# Generated deterministically by seda-macro-lef-normalizer-v1; recipe orfs-ng45-fakeram-metal3-coupledl2-pg-v1.
VERSION 5.8 ;
BUSBITCHARS "[]" ;
DIVIDERCHAR "/" ;

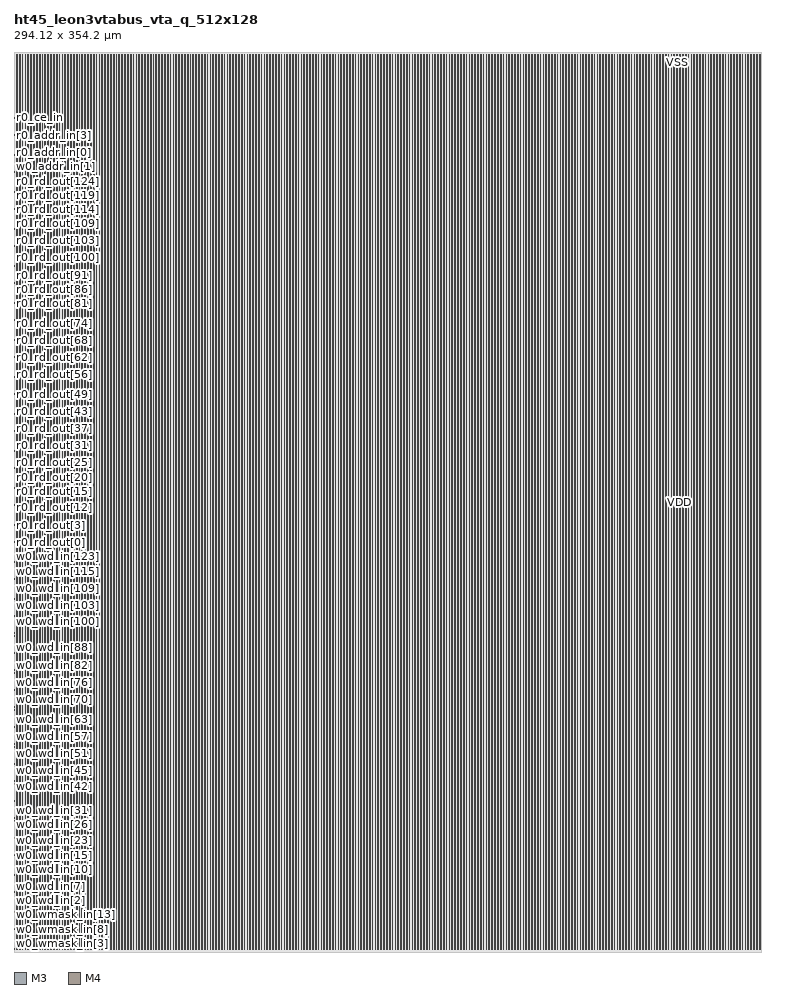
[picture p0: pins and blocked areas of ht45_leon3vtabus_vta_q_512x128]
MACRO ht45_leon3vtabus_vta_q_512x128
  FOREIGN ht45_leon3vtabus_vta_q_512x128 0 0 ;
  CLASS BLOCK ;
  ORIGIN 0 0 ;
  SIZE 294.12 BY 354.2 ;
  SYMMETRY X Y R90 ;
  PIN w0_wmask_in[0]
    DIRECTION INPUT ;
    USE SIGNAL ;
    SHAPE ABUTMENT ;
    PORT
      LAYER M3 ;
      RECT 0 0.035 0.07 0.105 ;
    END
  END w0_wmask_in[0]
  PIN w0_wmask_in[1]
    DIRECTION INPUT ;
    USE SIGNAL ;
    SHAPE ABUTMENT ;
    PORT
      LAYER M3 ;
      RECT 0 1.155 0.07 1.225 ;
    END
  END w0_wmask_in[1]
  PIN w0_wmask_in[2]
    DIRECTION INPUT ;
    USE SIGNAL ;
    SHAPE ABUTMENT ;
    PORT
      LAYER M3 ;
      RECT 0 2.275 0.07 2.345 ;
    END
  END w0_wmask_in[2]
  PIN w0_wmask_in[3]
    DIRECTION INPUT ;
    USE SIGNAL ;
    SHAPE ABUTMENT ;
    PORT
      LAYER M3 ;
      RECT 0 3.395 0.07 3.465 ;
    END
  END w0_wmask_in[3]
  PIN w0_wmask_in[4]
    DIRECTION INPUT ;
    USE SIGNAL ;
    SHAPE ABUTMENT ;
    PORT
      LAYER M3 ;
      RECT 0 4.515 0.07 4.585 ;
    END
  END w0_wmask_in[4]
  PIN w0_wmask_in[5]
    DIRECTION INPUT ;
    USE SIGNAL ;
    SHAPE ABUTMENT ;
    PORT
      LAYER M3 ;
      RECT 0 5.635 0.07 5.705 ;
    END
  END w0_wmask_in[5]
  PIN w0_wmask_in[6]
    DIRECTION INPUT ;
    USE SIGNAL ;
    SHAPE ABUTMENT ;
    PORT
      LAYER M3 ;
      RECT 0 6.755 0.07 6.825 ;
    END
  END w0_wmask_in[6]
  PIN w0_wmask_in[7]
    DIRECTION INPUT ;
    USE SIGNAL ;
    SHAPE ABUTMENT ;
    PORT
      LAYER M3 ;
      RECT 0 7.875 0.07 7.945 ;
    END
  END w0_wmask_in[7]
  PIN w0_wmask_in[8]
    DIRECTION INPUT ;
    USE SIGNAL ;
    SHAPE ABUTMENT ;
    PORT
      LAYER M3 ;
      RECT 0 8.995 0.07 9.065 ;
    END
  END w0_wmask_in[8]
  PIN w0_wmask_in[9]
    DIRECTION INPUT ;
    USE SIGNAL ;
    SHAPE ABUTMENT ;
    PORT
      LAYER M3 ;
      RECT 0 10.115 0.07 10.185 ;
    END
  END w0_wmask_in[9]
  PIN w0_wmask_in[10]
    DIRECTION INPUT ;
    USE SIGNAL ;
    SHAPE ABUTMENT ;
    PORT
      LAYER M3 ;
      RECT 0 11.235 0.07 11.305 ;
    END
  END w0_wmask_in[10]
  PIN w0_wmask_in[11]
    DIRECTION INPUT ;
    USE SIGNAL ;
    SHAPE ABUTMENT ;
    PORT
      LAYER M3 ;
      RECT 0 12.355 0.07 12.425 ;
    END
  END w0_wmask_in[11]
  PIN w0_wmask_in[12]
    DIRECTION INPUT ;
    USE SIGNAL ;
    SHAPE ABUTMENT ;
    PORT
      LAYER M3 ;
      RECT 0 13.475 0.07 13.545 ;
    END
  END w0_wmask_in[12]
  PIN w0_wmask_in[13]
    DIRECTION INPUT ;
    USE SIGNAL ;
    SHAPE ABUTMENT ;
    PORT
      LAYER M3 ;
      RECT 0 14.595 0.07 14.665 ;
    END
  END w0_wmask_in[13]
  PIN w0_wmask_in[14]
    DIRECTION INPUT ;
    USE SIGNAL ;
    SHAPE ABUTMENT ;
    PORT
      LAYER M3 ;
      RECT 0 15.715 0.07 15.785 ;
    END
  END w0_wmask_in[14]
  PIN w0_wmask_in[15]
    DIRECTION INPUT ;
    USE SIGNAL ;
    SHAPE ABUTMENT ;
    PORT
      LAYER M3 ;
      RECT 0 16.835 0.07 16.905 ;
    END
  END w0_wmask_in[15]
  PIN w0_wd_in[0]
    DIRECTION INPUT ;
    USE SIGNAL ;
    SHAPE ABUTMENT ;
    PORT
      LAYER M3 ;
      RECT 0 17.955 0.07 18.025 ;
    END
  END w0_wd_in[0]
  PIN w0_wd_in[1]
    DIRECTION INPUT ;
    USE SIGNAL ;
    SHAPE ABUTMENT ;
    PORT
      LAYER M3 ;
      RECT 0 19.075 0.07 19.145 ;
    END
  END w0_wd_in[1]
  PIN w0_wd_in[2]
    DIRECTION INPUT ;
    USE SIGNAL ;
    SHAPE ABUTMENT ;
    PORT
      LAYER M3 ;
      RECT 0 20.195 0.07 20.265 ;
    END
  END w0_wd_in[2]
  PIN w0_wd_in[3]
    DIRECTION INPUT ;
    USE SIGNAL ;
    SHAPE ABUTMENT ;
    PORT
      LAYER M3 ;
      RECT 0 21.315 0.07 21.385 ;
    END
  END w0_wd_in[3]
  PIN w0_wd_in[4]
    DIRECTION INPUT ;
    USE SIGNAL ;
    SHAPE ABUTMENT ;
    PORT
      LAYER M3 ;
      RECT 0 22.435 0.07 22.505 ;
    END
  END w0_wd_in[4]
  PIN w0_wd_in[5]
    DIRECTION INPUT ;
    USE SIGNAL ;
    SHAPE ABUTMENT ;
    PORT
      LAYER M3 ;
      RECT 0 23.555 0.07 23.625 ;
    END
  END w0_wd_in[5]
  PIN w0_wd_in[6]
    DIRECTION INPUT ;
    USE SIGNAL ;
    SHAPE ABUTMENT ;
    PORT
      LAYER M3 ;
      RECT 0 24.675 0.07 24.745 ;
    END
  END w0_wd_in[6]
  PIN w0_wd_in[7]
    DIRECTION INPUT ;
    USE SIGNAL ;
    SHAPE ABUTMENT ;
    PORT
      LAYER M3 ;
      RECT 0 25.795 0.07 25.865 ;
    END
  END w0_wd_in[7]
  PIN w0_wd_in[8]
    DIRECTION INPUT ;
    USE SIGNAL ;
    SHAPE ABUTMENT ;
    PORT
      LAYER M3 ;
      RECT 0 26.915 0.07 26.985 ;
    END
  END w0_wd_in[8]
  PIN w0_wd_in[9]
    DIRECTION INPUT ;
    USE SIGNAL ;
    SHAPE ABUTMENT ;
    PORT
      LAYER M3 ;
      RECT 0 28.035 0.07 28.105 ;
    END
  END w0_wd_in[9]
  PIN w0_wd_in[10]
    DIRECTION INPUT ;
    USE SIGNAL ;
    SHAPE ABUTMENT ;
    PORT
      LAYER M3 ;
      RECT 0 29.155 0.07 29.225 ;
    END
  END w0_wd_in[10]
  PIN w0_wd_in[11]
    DIRECTION INPUT ;
    USE SIGNAL ;
    SHAPE ABUTMENT ;
    PORT
      LAYER M3 ;
      RECT 0 30.275 0.07 30.345 ;
    END
  END w0_wd_in[11]
  PIN w0_wd_in[12]
    DIRECTION INPUT ;
    USE SIGNAL ;
    SHAPE ABUTMENT ;
    PORT
      LAYER M3 ;
      RECT 0 31.395 0.07 31.465 ;
    END
  END w0_wd_in[12]
  PIN w0_wd_in[13]
    DIRECTION INPUT ;
    USE SIGNAL ;
    SHAPE ABUTMENT ;
    PORT
      LAYER M3 ;
      RECT 0 32.515 0.07 32.585 ;
    END
  END w0_wd_in[13]
  PIN w0_wd_in[14]
    DIRECTION INPUT ;
    USE SIGNAL ;
    SHAPE ABUTMENT ;
    PORT
      LAYER M3 ;
      RECT 0 33.635 0.07 33.705 ;
    END
  END w0_wd_in[14]
  PIN w0_wd_in[15]
    DIRECTION INPUT ;
    USE SIGNAL ;
    SHAPE ABUTMENT ;
    PORT
      LAYER M3 ;
      RECT 0 34.755 0.07 34.825 ;
    END
  END w0_wd_in[15]
  PIN w0_wd_in[16]
    DIRECTION INPUT ;
    USE SIGNAL ;
    SHAPE ABUTMENT ;
    PORT
      LAYER M3 ;
      RECT 0 35.875 0.07 35.945 ;
    END
  END w0_wd_in[16]
  PIN w0_wd_in[17]
    DIRECTION INPUT ;
    USE SIGNAL ;
    SHAPE ABUTMENT ;
    PORT
      LAYER M3 ;
      RECT 0 36.995 0.07 37.065 ;
    END
  END w0_wd_in[17]
  PIN w0_wd_in[18]
    DIRECTION INPUT ;
    USE SIGNAL ;
    SHAPE ABUTMENT ;
    PORT
      LAYER M3 ;
      RECT 0 38.115 0.07 38.185 ;
    END
  END w0_wd_in[18]
  PIN w0_wd_in[19]
    DIRECTION INPUT ;
    USE SIGNAL ;
    SHAPE ABUTMENT ;
    PORT
      LAYER M3 ;
      RECT 0 39.235 0.07 39.305 ;
    END
  END w0_wd_in[19]
  PIN w0_wd_in[20]
    DIRECTION INPUT ;
    USE SIGNAL ;
    SHAPE ABUTMENT ;
    PORT
      LAYER M3 ;
      RECT 0 40.355 0.07 40.425 ;
    END
  END w0_wd_in[20]
  PIN w0_wd_in[21]
    DIRECTION INPUT ;
    USE SIGNAL ;
    SHAPE ABUTMENT ;
    PORT
      LAYER M3 ;
      RECT 0 41.475 0.07 41.545 ;
    END
  END w0_wd_in[21]
  PIN w0_wd_in[22]
    DIRECTION INPUT ;
    USE SIGNAL ;
    SHAPE ABUTMENT ;
    PORT
      LAYER M3 ;
      RECT 0 42.595 0.07 42.665 ;
    END
  END w0_wd_in[22]
  PIN w0_wd_in[23]
    DIRECTION INPUT ;
    USE SIGNAL ;
    SHAPE ABUTMENT ;
    PORT
      LAYER M3 ;
      RECT 0 43.715 0.07 43.785 ;
    END
  END w0_wd_in[23]
  PIN w0_wd_in[24]
    DIRECTION INPUT ;
    USE SIGNAL ;
    SHAPE ABUTMENT ;
    PORT
      LAYER M3 ;
      RECT 0 44.835 0.07 44.905 ;
    END
  END w0_wd_in[24]
  PIN w0_wd_in[25]
    DIRECTION INPUT ;
    USE SIGNAL ;
    SHAPE ABUTMENT ;
    PORT
      LAYER M3 ;
      RECT 0 45.955 0.07 46.025 ;
    END
  END w0_wd_in[25]
  PIN w0_wd_in[26]
    DIRECTION INPUT ;
    USE SIGNAL ;
    SHAPE ABUTMENT ;
    PORT
      LAYER M3 ;
      RECT 0 47.075 0.07 47.145 ;
    END
  END w0_wd_in[26]
  PIN w0_wd_in[27]
    DIRECTION INPUT ;
    USE SIGNAL ;
    SHAPE ABUTMENT ;
    PORT
      LAYER M3 ;
      RECT 0 48.195 0.07 48.265 ;
    END
  END w0_wd_in[27]
  PIN w0_wd_in[28]
    DIRECTION INPUT ;
    USE SIGNAL ;
    SHAPE ABUTMENT ;
    PORT
      LAYER M3 ;
      RECT 0 49.315 0.07 49.385 ;
    END
  END w0_wd_in[28]
  PIN w0_wd_in[29]
    DIRECTION INPUT ;
    USE SIGNAL ;
    SHAPE ABUTMENT ;
    PORT
      LAYER M3 ;
      RECT 0 50.435 0.07 50.505 ;
    END
  END w0_wd_in[29]
  PIN w0_wd_in[30]
    DIRECTION INPUT ;
    USE SIGNAL ;
    SHAPE ABUTMENT ;
    PORT
      LAYER M3 ;
      RECT 0 51.555 0.07 51.625 ;
    END
  END w0_wd_in[30]
  PIN w0_wd_in[31]
    DIRECTION INPUT ;
    USE SIGNAL ;
    SHAPE ABUTMENT ;
    PORT
      LAYER M3 ;
      RECT 0 52.675 0.07 52.745 ;
    END
  END w0_wd_in[31]
  PIN w0_wd_in[32]
    DIRECTION INPUT ;
    USE SIGNAL ;
    SHAPE ABUTMENT ;
    PORT
      LAYER M3 ;
      RECT 0 53.795 0.07 53.865 ;
    END
  END w0_wd_in[32]
  PIN w0_wd_in[33]
    DIRECTION INPUT ;
    USE SIGNAL ;
    SHAPE ABUTMENT ;
    PORT
      LAYER M3 ;
      RECT 0 54.915 0.07 54.985 ;
    END
  END w0_wd_in[33]
  PIN w0_wd_in[34]
    DIRECTION INPUT ;
    USE SIGNAL ;
    SHAPE ABUTMENT ;
    PORT
      LAYER M3 ;
      RECT 0 56.035 0.07 56.105 ;
    END
  END w0_wd_in[34]
  PIN w0_wd_in[35]
    DIRECTION INPUT ;
    USE SIGNAL ;
    SHAPE ABUTMENT ;
    PORT
      LAYER M3 ;
      RECT 0 57.155 0.07 57.225 ;
    END
  END w0_wd_in[35]
  PIN w0_wd_in[36]
    DIRECTION INPUT ;
    USE SIGNAL ;
    SHAPE ABUTMENT ;
    PORT
      LAYER M3 ;
      RECT 0 58.275 0.07 58.345 ;
    END
  END w0_wd_in[36]
  PIN w0_wd_in[37]
    DIRECTION INPUT ;
    USE SIGNAL ;
    SHAPE ABUTMENT ;
    PORT
      LAYER M3 ;
      RECT 0 59.395 0.07 59.465 ;
    END
  END w0_wd_in[37]
  PIN w0_wd_in[38]
    DIRECTION INPUT ;
    USE SIGNAL ;
    SHAPE ABUTMENT ;
    PORT
      LAYER M3 ;
      RECT 0 60.515 0.07 60.585 ;
    END
  END w0_wd_in[38]
  PIN w0_wd_in[39]
    DIRECTION INPUT ;
    USE SIGNAL ;
    SHAPE ABUTMENT ;
    PORT
      LAYER M3 ;
      RECT 0 61.635 0.07 61.705 ;
    END
  END w0_wd_in[39]
  PIN w0_wd_in[40]
    DIRECTION INPUT ;
    USE SIGNAL ;
    SHAPE ABUTMENT ;
    PORT
      LAYER M3 ;
      RECT 0 62.755 0.07 62.825 ;
    END
  END w0_wd_in[40]
  PIN w0_wd_in[41]
    DIRECTION INPUT ;
    USE SIGNAL ;
    SHAPE ABUTMENT ;
    PORT
      LAYER M3 ;
      RECT 0 63.875 0.07 63.945 ;
    END
  END w0_wd_in[41]
  PIN w0_wd_in[42]
    DIRECTION INPUT ;
    USE SIGNAL ;
    SHAPE ABUTMENT ;
    PORT
      LAYER M3 ;
      RECT 0 64.995 0.07 65.065 ;
    END
  END w0_wd_in[42]
  PIN w0_wd_in[43]
    DIRECTION INPUT ;
    USE SIGNAL ;
    SHAPE ABUTMENT ;
    PORT
      LAYER M3 ;
      RECT 0 66.115 0.07 66.185 ;
    END
  END w0_wd_in[43]
  PIN w0_wd_in[44]
    DIRECTION INPUT ;
    USE SIGNAL ;
    SHAPE ABUTMENT ;
    PORT
      LAYER M3 ;
      RECT 0 67.235 0.07 67.305 ;
    END
  END w0_wd_in[44]
  PIN w0_wd_in[45]
    DIRECTION INPUT ;
    USE SIGNAL ;
    SHAPE ABUTMENT ;
    PORT
      LAYER M3 ;
      RECT 0 68.355 0.07 68.425 ;
    END
  END w0_wd_in[45]
  PIN w0_wd_in[46]
    DIRECTION INPUT ;
    USE SIGNAL ;
    SHAPE ABUTMENT ;
    PORT
      LAYER M3 ;
      RECT 0 69.475 0.07 69.545 ;
    END
  END w0_wd_in[46]
  PIN w0_wd_in[47]
    DIRECTION INPUT ;
    USE SIGNAL ;
    SHAPE ABUTMENT ;
    PORT
      LAYER M3 ;
      RECT 0 70.595 0.07 70.665 ;
    END
  END w0_wd_in[47]
  PIN w0_wd_in[48]
    DIRECTION INPUT ;
    USE SIGNAL ;
    SHAPE ABUTMENT ;
    PORT
      LAYER M3 ;
      RECT 0 71.715 0.07 71.785 ;
    END
  END w0_wd_in[48]
  PIN w0_wd_in[49]
    DIRECTION INPUT ;
    USE SIGNAL ;
    SHAPE ABUTMENT ;
    PORT
      LAYER M3 ;
      RECT 0 72.835 0.07 72.905 ;
    END
  END w0_wd_in[49]
  PIN w0_wd_in[50]
    DIRECTION INPUT ;
    USE SIGNAL ;
    SHAPE ABUTMENT ;
    PORT
      LAYER M3 ;
      RECT 0 73.955 0.07 74.025 ;
    END
  END w0_wd_in[50]
  PIN w0_wd_in[51]
    DIRECTION INPUT ;
    USE SIGNAL ;
    SHAPE ABUTMENT ;
    PORT
      LAYER M3 ;
      RECT 0 75.075 0.07 75.145 ;
    END
  END w0_wd_in[51]
  PIN w0_wd_in[52]
    DIRECTION INPUT ;
    USE SIGNAL ;
    SHAPE ABUTMENT ;
    PORT
      LAYER M3 ;
      RECT 0 76.195 0.07 76.265 ;
    END
  END w0_wd_in[52]
  PIN w0_wd_in[53]
    DIRECTION INPUT ;
    USE SIGNAL ;
    SHAPE ABUTMENT ;
    PORT
      LAYER M3 ;
      RECT 0 77.315 0.07 77.385 ;
    END
  END w0_wd_in[53]
  PIN w0_wd_in[54]
    DIRECTION INPUT ;
    USE SIGNAL ;
    SHAPE ABUTMENT ;
    PORT
      LAYER M3 ;
      RECT 0 78.435 0.07 78.505 ;
    END
  END w0_wd_in[54]
  PIN w0_wd_in[55]
    DIRECTION INPUT ;
    USE SIGNAL ;
    SHAPE ABUTMENT ;
    PORT
      LAYER M3 ;
      RECT 0 79.555 0.07 79.625 ;
    END
  END w0_wd_in[55]
  PIN w0_wd_in[56]
    DIRECTION INPUT ;
    USE SIGNAL ;
    SHAPE ABUTMENT ;
    PORT
      LAYER M3 ;
      RECT 0 80.675 0.07 80.745 ;
    END
  END w0_wd_in[56]
  PIN w0_wd_in[57]
    DIRECTION INPUT ;
    USE SIGNAL ;
    SHAPE ABUTMENT ;
    PORT
      LAYER M3 ;
      RECT 0 81.795 0.07 81.865 ;
    END
  END w0_wd_in[57]
  PIN w0_wd_in[58]
    DIRECTION INPUT ;
    USE SIGNAL ;
    SHAPE ABUTMENT ;
    PORT
      LAYER M3 ;
      RECT 0 82.915 0.07 82.985 ;
    END
  END w0_wd_in[58]
  PIN w0_wd_in[59]
    DIRECTION INPUT ;
    USE SIGNAL ;
    SHAPE ABUTMENT ;
    PORT
      LAYER M3 ;
      RECT 0 84.035 0.07 84.105 ;
    END
  END w0_wd_in[59]
  PIN w0_wd_in[60]
    DIRECTION INPUT ;
    USE SIGNAL ;
    SHAPE ABUTMENT ;
    PORT
      LAYER M3 ;
      RECT 0 85.155 0.07 85.225 ;
    END
  END w0_wd_in[60]
  PIN w0_wd_in[61]
    DIRECTION INPUT ;
    USE SIGNAL ;
    SHAPE ABUTMENT ;
    PORT
      LAYER M3 ;
      RECT 0 86.275 0.07 86.345 ;
    END
  END w0_wd_in[61]
  PIN w0_wd_in[62]
    DIRECTION INPUT ;
    USE SIGNAL ;
    SHAPE ABUTMENT ;
    PORT
      LAYER M3 ;
      RECT 0 87.395 0.07 87.465 ;
    END
  END w0_wd_in[62]
  PIN w0_wd_in[63]
    DIRECTION INPUT ;
    USE SIGNAL ;
    SHAPE ABUTMENT ;
    PORT
      LAYER M3 ;
      RECT 0 88.515 0.07 88.585 ;
    END
  END w0_wd_in[63]
  PIN w0_wd_in[64]
    DIRECTION INPUT ;
    USE SIGNAL ;
    SHAPE ABUTMENT ;
    PORT
      LAYER M3 ;
      RECT 0 89.635 0.07 89.705 ;
    END
  END w0_wd_in[64]
  PIN w0_wd_in[65]
    DIRECTION INPUT ;
    USE SIGNAL ;
    SHAPE ABUTMENT ;
    PORT
      LAYER M3 ;
      RECT 0 90.755 0.07 90.825 ;
    END
  END w0_wd_in[65]
  PIN w0_wd_in[66]
    DIRECTION INPUT ;
    USE SIGNAL ;
    SHAPE ABUTMENT ;
    PORT
      LAYER M3 ;
      RECT 0 91.875 0.07 91.945 ;
    END
  END w0_wd_in[66]
  PIN w0_wd_in[67]
    DIRECTION INPUT ;
    USE SIGNAL ;
    SHAPE ABUTMENT ;
    PORT
      LAYER M3 ;
      RECT 0 92.995 0.07 93.065 ;
    END
  END w0_wd_in[67]
  PIN w0_wd_in[68]
    DIRECTION INPUT ;
    USE SIGNAL ;
    SHAPE ABUTMENT ;
    PORT
      LAYER M3 ;
      RECT 0 94.115 0.07 94.185 ;
    END
  END w0_wd_in[68]
  PIN w0_wd_in[69]
    DIRECTION INPUT ;
    USE SIGNAL ;
    SHAPE ABUTMENT ;
    PORT
      LAYER M3 ;
      RECT 0 95.235 0.07 95.305 ;
    END
  END w0_wd_in[69]
  PIN w0_wd_in[70]
    DIRECTION INPUT ;
    USE SIGNAL ;
    SHAPE ABUTMENT ;
    PORT
      LAYER M3 ;
      RECT 0 96.355 0.07 96.425 ;
    END
  END w0_wd_in[70]
  PIN w0_wd_in[71]
    DIRECTION INPUT ;
    USE SIGNAL ;
    SHAPE ABUTMENT ;
    PORT
      LAYER M3 ;
      RECT 0 97.475 0.07 97.545 ;
    END
  END w0_wd_in[71]
  PIN w0_wd_in[72]
    DIRECTION INPUT ;
    USE SIGNAL ;
    SHAPE ABUTMENT ;
    PORT
      LAYER M3 ;
      RECT 0 98.595 0.07 98.665 ;
    END
  END w0_wd_in[72]
  PIN w0_wd_in[73]
    DIRECTION INPUT ;
    USE SIGNAL ;
    SHAPE ABUTMENT ;
    PORT
      LAYER M3 ;
      RECT 0 99.715 0.07 99.785 ;
    END
  END w0_wd_in[73]
  PIN w0_wd_in[74]
    DIRECTION INPUT ;
    USE SIGNAL ;
    SHAPE ABUTMENT ;
    PORT
      LAYER M3 ;
      RECT 0 100.835 0.07 100.905 ;
    END
  END w0_wd_in[74]
  PIN w0_wd_in[75]
    DIRECTION INPUT ;
    USE SIGNAL ;
    SHAPE ABUTMENT ;
    PORT
      LAYER M3 ;
      RECT 0 101.955 0.07 102.025 ;
    END
  END w0_wd_in[75]
  PIN w0_wd_in[76]
    DIRECTION INPUT ;
    USE SIGNAL ;
    SHAPE ABUTMENT ;
    PORT
      LAYER M3 ;
      RECT 0 103.075 0.07 103.145 ;
    END
  END w0_wd_in[76]
  PIN w0_wd_in[77]
    DIRECTION INPUT ;
    USE SIGNAL ;
    SHAPE ABUTMENT ;
    PORT
      LAYER M3 ;
      RECT 0 104.195 0.07 104.265 ;
    END
  END w0_wd_in[77]
  PIN w0_wd_in[78]
    DIRECTION INPUT ;
    USE SIGNAL ;
    SHAPE ABUTMENT ;
    PORT
      LAYER M3 ;
      RECT 0 105.315 0.07 105.385 ;
    END
  END w0_wd_in[78]
  PIN w0_wd_in[79]
    DIRECTION INPUT ;
    USE SIGNAL ;
    SHAPE ABUTMENT ;
    PORT
      LAYER M3 ;
      RECT 0 106.435 0.07 106.505 ;
    END
  END w0_wd_in[79]
  PIN w0_wd_in[80]
    DIRECTION INPUT ;
    USE SIGNAL ;
    SHAPE ABUTMENT ;
    PORT
      LAYER M3 ;
      RECT 0 107.555 0.07 107.625 ;
    END
  END w0_wd_in[80]
  PIN w0_wd_in[81]
    DIRECTION INPUT ;
    USE SIGNAL ;
    SHAPE ABUTMENT ;
    PORT
      LAYER M3 ;
      RECT 0 108.675 0.07 108.745 ;
    END
  END w0_wd_in[81]
  PIN w0_wd_in[82]
    DIRECTION INPUT ;
    USE SIGNAL ;
    SHAPE ABUTMENT ;
    PORT
      LAYER M3 ;
      RECT 0 109.795 0.07 109.865 ;
    END
  END w0_wd_in[82]
  PIN w0_wd_in[83]
    DIRECTION INPUT ;
    USE SIGNAL ;
    SHAPE ABUTMENT ;
    PORT
      LAYER M3 ;
      RECT 0 110.915 0.07 110.985 ;
    END
  END w0_wd_in[83]
  PIN w0_wd_in[84]
    DIRECTION INPUT ;
    USE SIGNAL ;
    SHAPE ABUTMENT ;
    PORT
      LAYER M3 ;
      RECT 0 112.035 0.07 112.105 ;
    END
  END w0_wd_in[84]
  PIN w0_wd_in[85]
    DIRECTION INPUT ;
    USE SIGNAL ;
    SHAPE ABUTMENT ;
    PORT
      LAYER M3 ;
      RECT 0 113.155 0.07 113.225 ;
    END
  END w0_wd_in[85]
  PIN w0_wd_in[86]
    DIRECTION INPUT ;
    USE SIGNAL ;
    SHAPE ABUTMENT ;
    PORT
      LAYER M3 ;
      RECT 0 114.275 0.07 114.345 ;
    END
  END w0_wd_in[86]
  PIN w0_wd_in[87]
    DIRECTION INPUT ;
    USE SIGNAL ;
    SHAPE ABUTMENT ;
    PORT
      LAYER M3 ;
      RECT 0 115.395 0.07 115.465 ;
    END
  END w0_wd_in[87]
  PIN w0_wd_in[88]
    DIRECTION INPUT ;
    USE SIGNAL ;
    SHAPE ABUTMENT ;
    PORT
      LAYER M3 ;
      RECT 0 116.515 0.07 116.585 ;
    END
  END w0_wd_in[88]
  PIN w0_wd_in[89]
    DIRECTION INPUT ;
    USE SIGNAL ;
    SHAPE ABUTMENT ;
    PORT
      LAYER M3 ;
      RECT 0 117.635 0.07 117.705 ;
    END
  END w0_wd_in[89]
  PIN w0_wd_in[90]
    DIRECTION INPUT ;
    USE SIGNAL ;
    SHAPE ABUTMENT ;
    PORT
      LAYER M3 ;
      RECT 0 118.755 0.07 118.825 ;
    END
  END w0_wd_in[90]
  PIN w0_wd_in[91]
    DIRECTION INPUT ;
    USE SIGNAL ;
    SHAPE ABUTMENT ;
    PORT
      LAYER M3 ;
      RECT 0 119.875 0.07 119.945 ;
    END
  END w0_wd_in[91]
  PIN w0_wd_in[92]
    DIRECTION INPUT ;
    USE SIGNAL ;
    SHAPE ABUTMENT ;
    PORT
      LAYER M3 ;
      RECT 0 120.995 0.07 121.065 ;
    END
  END w0_wd_in[92]
  PIN w0_wd_in[93]
    DIRECTION INPUT ;
    USE SIGNAL ;
    SHAPE ABUTMENT ;
    PORT
      LAYER M3 ;
      RECT 0 122.115 0.07 122.185 ;
    END
  END w0_wd_in[93]
  PIN w0_wd_in[94]
    DIRECTION INPUT ;
    USE SIGNAL ;
    SHAPE ABUTMENT ;
    PORT
      LAYER M3 ;
      RECT 0 123.235 0.07 123.305 ;
    END
  END w0_wd_in[94]
  PIN w0_wd_in[95]
    DIRECTION INPUT ;
    USE SIGNAL ;
    SHAPE ABUTMENT ;
    PORT
      LAYER M3 ;
      RECT 0 124.355 0.07 124.425 ;
    END
  END w0_wd_in[95]
  PIN w0_wd_in[96]
    DIRECTION INPUT ;
    USE SIGNAL ;
    SHAPE ABUTMENT ;
    PORT
      LAYER M3 ;
      RECT 0 125.475 0.07 125.545 ;
    END
  END w0_wd_in[96]
  PIN w0_wd_in[97]
    DIRECTION INPUT ;
    USE SIGNAL ;
    SHAPE ABUTMENT ;
    PORT
      LAYER M3 ;
      RECT 0 126.595 0.07 126.665 ;
    END
  END w0_wd_in[97]
  PIN w0_wd_in[98]
    DIRECTION INPUT ;
    USE SIGNAL ;
    SHAPE ABUTMENT ;
    PORT
      LAYER M3 ;
      RECT 0 127.715 0.07 127.785 ;
    END
  END w0_wd_in[98]
  PIN w0_wd_in[99]
    DIRECTION INPUT ;
    USE SIGNAL ;
    SHAPE ABUTMENT ;
    PORT
      LAYER M3 ;
      RECT 0 128.835 0.07 128.905 ;
    END
  END w0_wd_in[99]
  PIN w0_wd_in[100]
    DIRECTION INPUT ;
    USE SIGNAL ;
    SHAPE ABUTMENT ;
    PORT
      LAYER M3 ;
      RECT 0 129.955 0.07 130.025 ;
    END
  END w0_wd_in[100]
  PIN w0_wd_in[101]
    DIRECTION INPUT ;
    USE SIGNAL ;
    SHAPE ABUTMENT ;
    PORT
      LAYER M3 ;
      RECT 0 131.075 0.07 131.145 ;
    END
  END w0_wd_in[101]
  PIN w0_wd_in[102]
    DIRECTION INPUT ;
    USE SIGNAL ;
    SHAPE ABUTMENT ;
    PORT
      LAYER M3 ;
      RECT 0 132.195 0.07 132.265 ;
    END
  END w0_wd_in[102]
  PIN w0_wd_in[103]
    DIRECTION INPUT ;
    USE SIGNAL ;
    SHAPE ABUTMENT ;
    PORT
      LAYER M3 ;
      RECT 0 133.315 0.07 133.385 ;
    END
  END w0_wd_in[103]
  PIN w0_wd_in[104]
    DIRECTION INPUT ;
    USE SIGNAL ;
    SHAPE ABUTMENT ;
    PORT
      LAYER M3 ;
      RECT 0 134.435 0.07 134.505 ;
    END
  END w0_wd_in[104]
  PIN w0_wd_in[105]
    DIRECTION INPUT ;
    USE SIGNAL ;
    SHAPE ABUTMENT ;
    PORT
      LAYER M3 ;
      RECT 0 135.555 0.07 135.625 ;
    END
  END w0_wd_in[105]
  PIN w0_wd_in[106]
    DIRECTION INPUT ;
    USE SIGNAL ;
    SHAPE ABUTMENT ;
    PORT
      LAYER M3 ;
      RECT 0 136.675 0.07 136.745 ;
    END
  END w0_wd_in[106]
  PIN w0_wd_in[107]
    DIRECTION INPUT ;
    USE SIGNAL ;
    SHAPE ABUTMENT ;
    PORT
      LAYER M3 ;
      RECT 0 137.795 0.07 137.865 ;
    END
  END w0_wd_in[107]
  PIN w0_wd_in[108]
    DIRECTION INPUT ;
    USE SIGNAL ;
    SHAPE ABUTMENT ;
    PORT
      LAYER M3 ;
      RECT 0 138.915 0.07 138.985 ;
    END
  END w0_wd_in[108]
  PIN w0_wd_in[109]
    DIRECTION INPUT ;
    USE SIGNAL ;
    SHAPE ABUTMENT ;
    PORT
      LAYER M3 ;
      RECT 0 140.035 0.07 140.105 ;
    END
  END w0_wd_in[109]
  PIN w0_wd_in[110]
    DIRECTION INPUT ;
    USE SIGNAL ;
    SHAPE ABUTMENT ;
    PORT
      LAYER M3 ;
      RECT 0 141.155 0.07 141.225 ;
    END
  END w0_wd_in[110]
  PIN w0_wd_in[111]
    DIRECTION INPUT ;
    USE SIGNAL ;
    SHAPE ABUTMENT ;
    PORT
      LAYER M3 ;
      RECT 0 142.275 0.07 142.345 ;
    END
  END w0_wd_in[111]
  PIN w0_wd_in[112]
    DIRECTION INPUT ;
    USE SIGNAL ;
    SHAPE ABUTMENT ;
    PORT
      LAYER M3 ;
      RECT 0 143.395 0.07 143.465 ;
    END
  END w0_wd_in[112]
  PIN w0_wd_in[113]
    DIRECTION INPUT ;
    USE SIGNAL ;
    SHAPE ABUTMENT ;
    PORT
      LAYER M3 ;
      RECT 0 144.515 0.07 144.585 ;
    END
  END w0_wd_in[113]
  PIN w0_wd_in[114]
    DIRECTION INPUT ;
    USE SIGNAL ;
    SHAPE ABUTMENT ;
    PORT
      LAYER M3 ;
      RECT 0 145.635 0.07 145.705 ;
    END
  END w0_wd_in[114]
  PIN w0_wd_in[115]
    DIRECTION INPUT ;
    USE SIGNAL ;
    SHAPE ABUTMENT ;
    PORT
      LAYER M3 ;
      RECT 0 146.755 0.07 146.825 ;
    END
  END w0_wd_in[115]
  PIN w0_wd_in[116]
    DIRECTION INPUT ;
    USE SIGNAL ;
    SHAPE ABUTMENT ;
    PORT
      LAYER M3 ;
      RECT 0 147.875 0.07 147.945 ;
    END
  END w0_wd_in[116]
  PIN w0_wd_in[117]
    DIRECTION INPUT ;
    USE SIGNAL ;
    SHAPE ABUTMENT ;
    PORT
      LAYER M3 ;
      RECT 0 148.995 0.07 149.065 ;
    END
  END w0_wd_in[117]
  PIN w0_wd_in[118]
    DIRECTION INPUT ;
    USE SIGNAL ;
    SHAPE ABUTMENT ;
    PORT
      LAYER M3 ;
      RECT 0 150.115 0.07 150.185 ;
    END
  END w0_wd_in[118]
  PIN w0_wd_in[119]
    DIRECTION INPUT ;
    USE SIGNAL ;
    SHAPE ABUTMENT ;
    PORT
      LAYER M3 ;
      RECT 0 151.235 0.07 151.305 ;
    END
  END w0_wd_in[119]
  PIN w0_wd_in[120]
    DIRECTION INPUT ;
    USE SIGNAL ;
    SHAPE ABUTMENT ;
    PORT
      LAYER M3 ;
      RECT 0 152.355 0.07 152.425 ;
    END
  END w0_wd_in[120]
  PIN w0_wd_in[121]
    DIRECTION INPUT ;
    USE SIGNAL ;
    SHAPE ABUTMENT ;
    PORT
      LAYER M3 ;
      RECT 0 153.475 0.07 153.545 ;
    END
  END w0_wd_in[121]
  PIN w0_wd_in[122]
    DIRECTION INPUT ;
    USE SIGNAL ;
    SHAPE ABUTMENT ;
    PORT
      LAYER M3 ;
      RECT 0 154.595 0.07 154.665 ;
    END
  END w0_wd_in[122]
  PIN w0_wd_in[123]
    DIRECTION INPUT ;
    USE SIGNAL ;
    SHAPE ABUTMENT ;
    PORT
      LAYER M3 ;
      RECT 0 155.715 0.07 155.785 ;
    END
  END w0_wd_in[123]
  PIN w0_wd_in[124]
    DIRECTION INPUT ;
    USE SIGNAL ;
    SHAPE ABUTMENT ;
    PORT
      LAYER M3 ;
      RECT 0 156.835 0.07 156.905 ;
    END
  END w0_wd_in[124]
  PIN w0_wd_in[125]
    DIRECTION INPUT ;
    USE SIGNAL ;
    SHAPE ABUTMENT ;
    PORT
      LAYER M3 ;
      RECT 0 157.955 0.07 158.025 ;
    END
  END w0_wd_in[125]
  PIN w0_wd_in[126]
    DIRECTION INPUT ;
    USE SIGNAL ;
    SHAPE ABUTMENT ;
    PORT
      LAYER M3 ;
      RECT 0 159.075 0.07 159.145 ;
    END
  END w0_wd_in[126]
  PIN w0_wd_in[127]
    DIRECTION INPUT ;
    USE SIGNAL ;
    SHAPE ABUTMENT ;
    PORT
      LAYER M3 ;
      RECT 0 160.195 0.07 160.265 ;
    END
  END w0_wd_in[127]
  PIN r0_rd_out[0]
    DIRECTION OUTPUT ;
    USE SIGNAL ;
    SHAPE ABUTMENT ;
    PORT
      LAYER M3 ;
      RECT 0 161.315 0.07 161.385 ;
    END
  END r0_rd_out[0]
  PIN r0_rd_out[1]
    DIRECTION OUTPUT ;
    USE SIGNAL ;
    SHAPE ABUTMENT ;
    PORT
      LAYER M3 ;
      RECT 0 162.435 0.07 162.505 ;
    END
  END r0_rd_out[1]
  PIN r0_rd_out[2]
    DIRECTION OUTPUT ;
    USE SIGNAL ;
    SHAPE ABUTMENT ;
    PORT
      LAYER M3 ;
      RECT 0 163.555 0.07 163.625 ;
    END
  END r0_rd_out[2]
  PIN r0_rd_out[3]
    DIRECTION OUTPUT ;
    USE SIGNAL ;
    SHAPE ABUTMENT ;
    PORT
      LAYER M3 ;
      RECT 0 164.675 0.07 164.745 ;
    END
  END r0_rd_out[3]
  PIN r0_rd_out[4]
    DIRECTION OUTPUT ;
    USE SIGNAL ;
    SHAPE ABUTMENT ;
    PORT
      LAYER M3 ;
      RECT 0 165.795 0.07 165.865 ;
    END
  END r0_rd_out[4]
  PIN r0_rd_out[5]
    DIRECTION OUTPUT ;
    USE SIGNAL ;
    SHAPE ABUTMENT ;
    PORT
      LAYER M3 ;
      RECT 0 166.915 0.07 166.985 ;
    END
  END r0_rd_out[5]
  PIN r0_rd_out[6]
    DIRECTION OUTPUT ;
    USE SIGNAL ;
    SHAPE ABUTMENT ;
    PORT
      LAYER M3 ;
      RECT 0 168.035 0.07 168.105 ;
    END
  END r0_rd_out[6]
  PIN r0_rd_out[7]
    DIRECTION OUTPUT ;
    USE SIGNAL ;
    SHAPE ABUTMENT ;
    PORT
      LAYER M3 ;
      RECT 0 169.155 0.07 169.225 ;
    END
  END r0_rd_out[7]
  PIN r0_rd_out[8]
    DIRECTION OUTPUT ;
    USE SIGNAL ;
    SHAPE ABUTMENT ;
    PORT
      LAYER M3 ;
      RECT 0 170.275 0.07 170.345 ;
    END
  END r0_rd_out[8]
  PIN r0_rd_out[9]
    DIRECTION OUTPUT ;
    USE SIGNAL ;
    SHAPE ABUTMENT ;
    PORT
      LAYER M3 ;
      RECT 0 171.395 0.07 171.465 ;
    END
  END r0_rd_out[9]
  PIN r0_rd_out[10]
    DIRECTION OUTPUT ;
    USE SIGNAL ;
    SHAPE ABUTMENT ;
    PORT
      LAYER M3 ;
      RECT 0 172.515 0.07 172.585 ;
    END
  END r0_rd_out[10]
  PIN r0_rd_out[11]
    DIRECTION OUTPUT ;
    USE SIGNAL ;
    SHAPE ABUTMENT ;
    PORT
      LAYER M3 ;
      RECT 0 173.635 0.07 173.705 ;
    END
  END r0_rd_out[11]
  PIN r0_rd_out[12]
    DIRECTION OUTPUT ;
    USE SIGNAL ;
    SHAPE ABUTMENT ;
    PORT
      LAYER M3 ;
      RECT 0 174.755 0.07 174.825 ;
    END
  END r0_rd_out[12]
  PIN r0_rd_out[13]
    DIRECTION OUTPUT ;
    USE SIGNAL ;
    SHAPE ABUTMENT ;
    PORT
      LAYER M3 ;
      RECT 0 175.875 0.07 175.945 ;
    END
  END r0_rd_out[13]
  PIN r0_rd_out[14]
    DIRECTION OUTPUT ;
    USE SIGNAL ;
    SHAPE ABUTMENT ;
    PORT
      LAYER M3 ;
      RECT 0 176.995 0.07 177.065 ;
    END
  END r0_rd_out[14]
  PIN r0_rd_out[15]
    DIRECTION OUTPUT ;
    USE SIGNAL ;
    SHAPE ABUTMENT ;
    PORT
      LAYER M3 ;
      RECT 0 178.115 0.07 178.185 ;
    END
  END r0_rd_out[15]
  PIN r0_rd_out[16]
    DIRECTION OUTPUT ;
    USE SIGNAL ;
    SHAPE ABUTMENT ;
    PORT
      LAYER M3 ;
      RECT 0 179.235 0.07 179.305 ;
    END
  END r0_rd_out[16]
  PIN r0_rd_out[17]
    DIRECTION OUTPUT ;
    USE SIGNAL ;
    SHAPE ABUTMENT ;
    PORT
      LAYER M3 ;
      RECT 0 180.355 0.07 180.425 ;
    END
  END r0_rd_out[17]
  PIN r0_rd_out[18]
    DIRECTION OUTPUT ;
    USE SIGNAL ;
    SHAPE ABUTMENT ;
    PORT
      LAYER M3 ;
      RECT 0 181.475 0.07 181.545 ;
    END
  END r0_rd_out[18]
  PIN r0_rd_out[19]
    DIRECTION OUTPUT ;
    USE SIGNAL ;
    SHAPE ABUTMENT ;
    PORT
      LAYER M3 ;
      RECT 0 182.595 0.07 182.665 ;
    END
  END r0_rd_out[19]
  PIN r0_rd_out[20]
    DIRECTION OUTPUT ;
    USE SIGNAL ;
    SHAPE ABUTMENT ;
    PORT
      LAYER M3 ;
      RECT 0 183.715 0.07 183.785 ;
    END
  END r0_rd_out[20]
  PIN r0_rd_out[21]
    DIRECTION OUTPUT ;
    USE SIGNAL ;
    SHAPE ABUTMENT ;
    PORT
      LAYER M3 ;
      RECT 0 184.835 0.07 184.905 ;
    END
  END r0_rd_out[21]
  PIN r0_rd_out[22]
    DIRECTION OUTPUT ;
    USE SIGNAL ;
    SHAPE ABUTMENT ;
    PORT
      LAYER M3 ;
      RECT 0 185.955 0.07 186.025 ;
    END
  END r0_rd_out[22]
  PIN r0_rd_out[23]
    DIRECTION OUTPUT ;
    USE SIGNAL ;
    SHAPE ABUTMENT ;
    PORT
      LAYER M3 ;
      RECT 0 187.075 0.07 187.145 ;
    END
  END r0_rd_out[23]
  PIN r0_rd_out[24]
    DIRECTION OUTPUT ;
    USE SIGNAL ;
    SHAPE ABUTMENT ;
    PORT
      LAYER M3 ;
      RECT 0 188.195 0.07 188.265 ;
    END
  END r0_rd_out[24]
  PIN r0_rd_out[25]
    DIRECTION OUTPUT ;
    USE SIGNAL ;
    SHAPE ABUTMENT ;
    PORT
      LAYER M3 ;
      RECT 0 189.315 0.07 189.385 ;
    END
  END r0_rd_out[25]
  PIN r0_rd_out[26]
    DIRECTION OUTPUT ;
    USE SIGNAL ;
    SHAPE ABUTMENT ;
    PORT
      LAYER M3 ;
      RECT 0 190.435 0.07 190.505 ;
    END
  END r0_rd_out[26]
  PIN r0_rd_out[27]
    DIRECTION OUTPUT ;
    USE SIGNAL ;
    SHAPE ABUTMENT ;
    PORT
      LAYER M3 ;
      RECT 0 191.555 0.07 191.625 ;
    END
  END r0_rd_out[27]
  PIN r0_rd_out[28]
    DIRECTION OUTPUT ;
    USE SIGNAL ;
    SHAPE ABUTMENT ;
    PORT
      LAYER M3 ;
      RECT 0 192.675 0.07 192.745 ;
    END
  END r0_rd_out[28]
  PIN r0_rd_out[29]
    DIRECTION OUTPUT ;
    USE SIGNAL ;
    SHAPE ABUTMENT ;
    PORT
      LAYER M3 ;
      RECT 0 193.795 0.07 193.865 ;
    END
  END r0_rd_out[29]
  PIN r0_rd_out[30]
    DIRECTION OUTPUT ;
    USE SIGNAL ;
    SHAPE ABUTMENT ;
    PORT
      LAYER M3 ;
      RECT 0 194.915 0.07 194.985 ;
    END
  END r0_rd_out[30]
  PIN r0_rd_out[31]
    DIRECTION OUTPUT ;
    USE SIGNAL ;
    SHAPE ABUTMENT ;
    PORT
      LAYER M3 ;
      RECT 0 196.035 0.07 196.105 ;
    END
  END r0_rd_out[31]
  PIN r0_rd_out[32]
    DIRECTION OUTPUT ;
    USE SIGNAL ;
    SHAPE ABUTMENT ;
    PORT
      LAYER M3 ;
      RECT 0 197.155 0.07 197.225 ;
    END
  END r0_rd_out[32]
  PIN r0_rd_out[33]
    DIRECTION OUTPUT ;
    USE SIGNAL ;
    SHAPE ABUTMENT ;
    PORT
      LAYER M3 ;
      RECT 0 198.275 0.07 198.345 ;
    END
  END r0_rd_out[33]
  PIN r0_rd_out[34]
    DIRECTION OUTPUT ;
    USE SIGNAL ;
    SHAPE ABUTMENT ;
    PORT
      LAYER M3 ;
      RECT 0 199.395 0.07 199.465 ;
    END
  END r0_rd_out[34]
  PIN r0_rd_out[35]
    DIRECTION OUTPUT ;
    USE SIGNAL ;
    SHAPE ABUTMENT ;
    PORT
      LAYER M3 ;
      RECT 0 200.515 0.07 200.585 ;
    END
  END r0_rd_out[35]
  PIN r0_rd_out[36]
    DIRECTION OUTPUT ;
    USE SIGNAL ;
    SHAPE ABUTMENT ;
    PORT
      LAYER M3 ;
      RECT 0 201.635 0.07 201.705 ;
    END
  END r0_rd_out[36]
  PIN r0_rd_out[37]
    DIRECTION OUTPUT ;
    USE SIGNAL ;
    SHAPE ABUTMENT ;
    PORT
      LAYER M3 ;
      RECT 0 202.755 0.07 202.825 ;
    END
  END r0_rd_out[37]
  PIN r0_rd_out[38]
    DIRECTION OUTPUT ;
    USE SIGNAL ;
    SHAPE ABUTMENT ;
    PORT
      LAYER M3 ;
      RECT 0 203.875 0.07 203.945 ;
    END
  END r0_rd_out[38]
  PIN r0_rd_out[39]
    DIRECTION OUTPUT ;
    USE SIGNAL ;
    SHAPE ABUTMENT ;
    PORT
      LAYER M3 ;
      RECT 0 204.995 0.07 205.065 ;
    END
  END r0_rd_out[39]
  PIN r0_rd_out[40]
    DIRECTION OUTPUT ;
    USE SIGNAL ;
    SHAPE ABUTMENT ;
    PORT
      LAYER M3 ;
      RECT 0 206.115 0.07 206.185 ;
    END
  END r0_rd_out[40]
  PIN r0_rd_out[41]
    DIRECTION OUTPUT ;
    USE SIGNAL ;
    SHAPE ABUTMENT ;
    PORT
      LAYER M3 ;
      RECT 0 207.235 0.07 207.305 ;
    END
  END r0_rd_out[41]
  PIN r0_rd_out[42]
    DIRECTION OUTPUT ;
    USE SIGNAL ;
    SHAPE ABUTMENT ;
    PORT
      LAYER M3 ;
      RECT 0 208.355 0.07 208.425 ;
    END
  END r0_rd_out[42]
  PIN r0_rd_out[43]
    DIRECTION OUTPUT ;
    USE SIGNAL ;
    SHAPE ABUTMENT ;
    PORT
      LAYER M3 ;
      RECT 0 209.475 0.07 209.545 ;
    END
  END r0_rd_out[43]
  PIN r0_rd_out[44]
    DIRECTION OUTPUT ;
    USE SIGNAL ;
    SHAPE ABUTMENT ;
    PORT
      LAYER M3 ;
      RECT 0 210.595 0.07 210.665 ;
    END
  END r0_rd_out[44]
  PIN r0_rd_out[45]
    DIRECTION OUTPUT ;
    USE SIGNAL ;
    SHAPE ABUTMENT ;
    PORT
      LAYER M3 ;
      RECT 0 211.715 0.07 211.785 ;
    END
  END r0_rd_out[45]
  PIN r0_rd_out[46]
    DIRECTION OUTPUT ;
    USE SIGNAL ;
    SHAPE ABUTMENT ;
    PORT
      LAYER M3 ;
      RECT 0 212.835 0.07 212.905 ;
    END
  END r0_rd_out[46]
  PIN r0_rd_out[47]
    DIRECTION OUTPUT ;
    USE SIGNAL ;
    SHAPE ABUTMENT ;
    PORT
      LAYER M3 ;
      RECT 0 213.955 0.07 214.025 ;
    END
  END r0_rd_out[47]
  PIN r0_rd_out[48]
    DIRECTION OUTPUT ;
    USE SIGNAL ;
    SHAPE ABUTMENT ;
    PORT
      LAYER M3 ;
      RECT 0 215.075 0.07 215.145 ;
    END
  END r0_rd_out[48]
  PIN r0_rd_out[49]
    DIRECTION OUTPUT ;
    USE SIGNAL ;
    SHAPE ABUTMENT ;
    PORT
      LAYER M3 ;
      RECT 0 216.195 0.07 216.265 ;
    END
  END r0_rd_out[49]
  PIN r0_rd_out[50]
    DIRECTION OUTPUT ;
    USE SIGNAL ;
    SHAPE ABUTMENT ;
    PORT
      LAYER M3 ;
      RECT 0 217.315 0.07 217.385 ;
    END
  END r0_rd_out[50]
  PIN r0_rd_out[51]
    DIRECTION OUTPUT ;
    USE SIGNAL ;
    SHAPE ABUTMENT ;
    PORT
      LAYER M3 ;
      RECT 0 218.435 0.07 218.505 ;
    END
  END r0_rd_out[51]
  PIN r0_rd_out[52]
    DIRECTION OUTPUT ;
    USE SIGNAL ;
    SHAPE ABUTMENT ;
    PORT
      LAYER M3 ;
      RECT 0 219.555 0.07 219.625 ;
    END
  END r0_rd_out[52]
  PIN r0_rd_out[53]
    DIRECTION OUTPUT ;
    USE SIGNAL ;
    SHAPE ABUTMENT ;
    PORT
      LAYER M3 ;
      RECT 0 220.675 0.07 220.745 ;
    END
  END r0_rd_out[53]
  PIN r0_rd_out[54]
    DIRECTION OUTPUT ;
    USE SIGNAL ;
    SHAPE ABUTMENT ;
    PORT
      LAYER M3 ;
      RECT 0 221.795 0.07 221.865 ;
    END
  END r0_rd_out[54]
  PIN r0_rd_out[55]
    DIRECTION OUTPUT ;
    USE SIGNAL ;
    SHAPE ABUTMENT ;
    PORT
      LAYER M3 ;
      RECT 0 222.915 0.07 222.985 ;
    END
  END r0_rd_out[55]
  PIN r0_rd_out[56]
    DIRECTION OUTPUT ;
    USE SIGNAL ;
    SHAPE ABUTMENT ;
    PORT
      LAYER M3 ;
      RECT 0 224.035 0.07 224.105 ;
    END
  END r0_rd_out[56]
  PIN r0_rd_out[57]
    DIRECTION OUTPUT ;
    USE SIGNAL ;
    SHAPE ABUTMENT ;
    PORT
      LAYER M3 ;
      RECT 0 225.155 0.07 225.225 ;
    END
  END r0_rd_out[57]
  PIN r0_rd_out[58]
    DIRECTION OUTPUT ;
    USE SIGNAL ;
    SHAPE ABUTMENT ;
    PORT
      LAYER M3 ;
      RECT 0 226.275 0.07 226.345 ;
    END
  END r0_rd_out[58]
  PIN r0_rd_out[59]
    DIRECTION OUTPUT ;
    USE SIGNAL ;
    SHAPE ABUTMENT ;
    PORT
      LAYER M3 ;
      RECT 0 227.395 0.07 227.465 ;
    END
  END r0_rd_out[59]
  PIN r0_rd_out[60]
    DIRECTION OUTPUT ;
    USE SIGNAL ;
    SHAPE ABUTMENT ;
    PORT
      LAYER M3 ;
      RECT 0 228.515 0.07 228.585 ;
    END
  END r0_rd_out[60]
  PIN r0_rd_out[61]
    DIRECTION OUTPUT ;
    USE SIGNAL ;
    SHAPE ABUTMENT ;
    PORT
      LAYER M3 ;
      RECT 0 229.635 0.07 229.705 ;
    END
  END r0_rd_out[61]
  PIN r0_rd_out[62]
    DIRECTION OUTPUT ;
    USE SIGNAL ;
    SHAPE ABUTMENT ;
    PORT
      LAYER M3 ;
      RECT 0 230.755 0.07 230.825 ;
    END
  END r0_rd_out[62]
  PIN r0_rd_out[63]
    DIRECTION OUTPUT ;
    USE SIGNAL ;
    SHAPE ABUTMENT ;
    PORT
      LAYER M3 ;
      RECT 0 231.875 0.07 231.945 ;
    END
  END r0_rd_out[63]
  PIN r0_rd_out[64]
    DIRECTION OUTPUT ;
    USE SIGNAL ;
    SHAPE ABUTMENT ;
    PORT
      LAYER M3 ;
      RECT 0 232.995 0.07 233.065 ;
    END
  END r0_rd_out[64]
  PIN r0_rd_out[65]
    DIRECTION OUTPUT ;
    USE SIGNAL ;
    SHAPE ABUTMENT ;
    PORT
      LAYER M3 ;
      RECT 0 234.115 0.07 234.185 ;
    END
  END r0_rd_out[65]
  PIN r0_rd_out[66]
    DIRECTION OUTPUT ;
    USE SIGNAL ;
    SHAPE ABUTMENT ;
    PORT
      LAYER M3 ;
      RECT 0 235.235 0.07 235.305 ;
    END
  END r0_rd_out[66]
  PIN r0_rd_out[67]
    DIRECTION OUTPUT ;
    USE SIGNAL ;
    SHAPE ABUTMENT ;
    PORT
      LAYER M3 ;
      RECT 0 236.355 0.07 236.425 ;
    END
  END r0_rd_out[67]
  PIN r0_rd_out[68]
    DIRECTION OUTPUT ;
    USE SIGNAL ;
    SHAPE ABUTMENT ;
    PORT
      LAYER M3 ;
      RECT 0 237.475 0.07 237.545 ;
    END
  END r0_rd_out[68]
  PIN r0_rd_out[69]
    DIRECTION OUTPUT ;
    USE SIGNAL ;
    SHAPE ABUTMENT ;
    PORT
      LAYER M3 ;
      RECT 0 238.595 0.07 238.665 ;
    END
  END r0_rd_out[69]
  PIN r0_rd_out[70]
    DIRECTION OUTPUT ;
    USE SIGNAL ;
    SHAPE ABUTMENT ;
    PORT
      LAYER M3 ;
      RECT 0 239.715 0.07 239.785 ;
    END
  END r0_rd_out[70]
  PIN r0_rd_out[71]
    DIRECTION OUTPUT ;
    USE SIGNAL ;
    SHAPE ABUTMENT ;
    PORT
      LAYER M3 ;
      RECT 0 240.835 0.07 240.905 ;
    END
  END r0_rd_out[71]
  PIN r0_rd_out[72]
    DIRECTION OUTPUT ;
    USE SIGNAL ;
    SHAPE ABUTMENT ;
    PORT
      LAYER M3 ;
      RECT 0 241.955 0.07 242.025 ;
    END
  END r0_rd_out[72]
  PIN r0_rd_out[73]
    DIRECTION OUTPUT ;
    USE SIGNAL ;
    SHAPE ABUTMENT ;
    PORT
      LAYER M3 ;
      RECT 0 243.075 0.07 243.145 ;
    END
  END r0_rd_out[73]
  PIN r0_rd_out[74]
    DIRECTION OUTPUT ;
    USE SIGNAL ;
    SHAPE ABUTMENT ;
    PORT
      LAYER M3 ;
      RECT 0 244.195 0.07 244.265 ;
    END
  END r0_rd_out[74]
  PIN r0_rd_out[75]
    DIRECTION OUTPUT ;
    USE SIGNAL ;
    SHAPE ABUTMENT ;
    PORT
      LAYER M3 ;
      RECT 0 245.315 0.07 245.385 ;
    END
  END r0_rd_out[75]
  PIN r0_rd_out[76]
    DIRECTION OUTPUT ;
    USE SIGNAL ;
    SHAPE ABUTMENT ;
    PORT
      LAYER M3 ;
      RECT 0 246.435 0.07 246.505 ;
    END
  END r0_rd_out[76]
  PIN r0_rd_out[77]
    DIRECTION OUTPUT ;
    USE SIGNAL ;
    SHAPE ABUTMENT ;
    PORT
      LAYER M3 ;
      RECT 0 247.555 0.07 247.625 ;
    END
  END r0_rd_out[77]
  PIN r0_rd_out[78]
    DIRECTION OUTPUT ;
    USE SIGNAL ;
    SHAPE ABUTMENT ;
    PORT
      LAYER M3 ;
      RECT 0 248.675 0.07 248.745 ;
    END
  END r0_rd_out[78]
  PIN r0_rd_out[79]
    DIRECTION OUTPUT ;
    USE SIGNAL ;
    SHAPE ABUTMENT ;
    PORT
      LAYER M3 ;
      RECT 0 249.795 0.07 249.865 ;
    END
  END r0_rd_out[79]
  PIN r0_rd_out[80]
    DIRECTION OUTPUT ;
    USE SIGNAL ;
    SHAPE ABUTMENT ;
    PORT
      LAYER M3 ;
      RECT 0 250.915 0.07 250.985 ;
    END
  END r0_rd_out[80]
  PIN r0_rd_out[81]
    DIRECTION OUTPUT ;
    USE SIGNAL ;
    SHAPE ABUTMENT ;
    PORT
      LAYER M3 ;
      RECT 0 252.035 0.07 252.105 ;
    END
  END r0_rd_out[81]
  PIN r0_rd_out[82]
    DIRECTION OUTPUT ;
    USE SIGNAL ;
    SHAPE ABUTMENT ;
    PORT
      LAYER M3 ;
      RECT 0 253.155 0.07 253.225 ;
    END
  END r0_rd_out[82]
  PIN r0_rd_out[83]
    DIRECTION OUTPUT ;
    USE SIGNAL ;
    SHAPE ABUTMENT ;
    PORT
      LAYER M3 ;
      RECT 0 254.275 0.07 254.345 ;
    END
  END r0_rd_out[83]
  PIN r0_rd_out[84]
    DIRECTION OUTPUT ;
    USE SIGNAL ;
    SHAPE ABUTMENT ;
    PORT
      LAYER M3 ;
      RECT 0 255.395 0.07 255.465 ;
    END
  END r0_rd_out[84]
  PIN r0_rd_out[85]
    DIRECTION OUTPUT ;
    USE SIGNAL ;
    SHAPE ABUTMENT ;
    PORT
      LAYER M3 ;
      RECT 0 256.515 0.07 256.585 ;
    END
  END r0_rd_out[85]
  PIN r0_rd_out[86]
    DIRECTION OUTPUT ;
    USE SIGNAL ;
    SHAPE ABUTMENT ;
    PORT
      LAYER M3 ;
      RECT 0 257.635 0.07 257.705 ;
    END
  END r0_rd_out[86]
  PIN r0_rd_out[87]
    DIRECTION OUTPUT ;
    USE SIGNAL ;
    SHAPE ABUTMENT ;
    PORT
      LAYER M3 ;
      RECT 0 258.755 0.07 258.825 ;
    END
  END r0_rd_out[87]
  PIN r0_rd_out[88]
    DIRECTION OUTPUT ;
    USE SIGNAL ;
    SHAPE ABUTMENT ;
    PORT
      LAYER M3 ;
      RECT 0 259.875 0.07 259.945 ;
    END
  END r0_rd_out[88]
  PIN r0_rd_out[89]
    DIRECTION OUTPUT ;
    USE SIGNAL ;
    SHAPE ABUTMENT ;
    PORT
      LAYER M3 ;
      RECT 0 260.995 0.07 261.065 ;
    END
  END r0_rd_out[89]
  PIN r0_rd_out[90]
    DIRECTION OUTPUT ;
    USE SIGNAL ;
    SHAPE ABUTMENT ;
    PORT
      LAYER M3 ;
      RECT 0 262.115 0.07 262.185 ;
    END
  END r0_rd_out[90]
  PIN r0_rd_out[91]
    DIRECTION OUTPUT ;
    USE SIGNAL ;
    SHAPE ABUTMENT ;
    PORT
      LAYER M3 ;
      RECT 0 263.235 0.07 263.305 ;
    END
  END r0_rd_out[91]
  PIN r0_rd_out[92]
    DIRECTION OUTPUT ;
    USE SIGNAL ;
    SHAPE ABUTMENT ;
    PORT
      LAYER M3 ;
      RECT 0 264.355 0.07 264.425 ;
    END
  END r0_rd_out[92]
  PIN r0_rd_out[93]
    DIRECTION OUTPUT ;
    USE SIGNAL ;
    SHAPE ABUTMENT ;
    PORT
      LAYER M3 ;
      RECT 0 265.475 0.07 265.545 ;
    END
  END r0_rd_out[93]
  PIN r0_rd_out[94]
    DIRECTION OUTPUT ;
    USE SIGNAL ;
    SHAPE ABUTMENT ;
    PORT
      LAYER M3 ;
      RECT 0 266.595 0.07 266.665 ;
    END
  END r0_rd_out[94]
  PIN r0_rd_out[95]
    DIRECTION OUTPUT ;
    USE SIGNAL ;
    SHAPE ABUTMENT ;
    PORT
      LAYER M3 ;
      RECT 0 267.715 0.07 267.785 ;
    END
  END r0_rd_out[95]
  PIN r0_rd_out[96]
    DIRECTION OUTPUT ;
    USE SIGNAL ;
    SHAPE ABUTMENT ;
    PORT
      LAYER M3 ;
      RECT 0 268.835 0.07 268.905 ;
    END
  END r0_rd_out[96]
  PIN r0_rd_out[97]
    DIRECTION OUTPUT ;
    USE SIGNAL ;
    SHAPE ABUTMENT ;
    PORT
      LAYER M3 ;
      RECT 0 269.955 0.07 270.025 ;
    END
  END r0_rd_out[97]
  PIN r0_rd_out[98]
    DIRECTION OUTPUT ;
    USE SIGNAL ;
    SHAPE ABUTMENT ;
    PORT
      LAYER M3 ;
      RECT 0 271.075 0.07 271.145 ;
    END
  END r0_rd_out[98]
  PIN r0_rd_out[99]
    DIRECTION OUTPUT ;
    USE SIGNAL ;
    SHAPE ABUTMENT ;
    PORT
      LAYER M3 ;
      RECT 0 272.195 0.07 272.265 ;
    END
  END r0_rd_out[99]
  PIN r0_rd_out[100]
    DIRECTION OUTPUT ;
    USE SIGNAL ;
    SHAPE ABUTMENT ;
    PORT
      LAYER M3 ;
      RECT 0 273.315 0.07 273.385 ;
    END
  END r0_rd_out[100]
  PIN r0_rd_out[101]
    DIRECTION OUTPUT ;
    USE SIGNAL ;
    SHAPE ABUTMENT ;
    PORT
      LAYER M3 ;
      RECT 0 274.435 0.07 274.505 ;
    END
  END r0_rd_out[101]
  PIN r0_rd_out[102]
    DIRECTION OUTPUT ;
    USE SIGNAL ;
    SHAPE ABUTMENT ;
    PORT
      LAYER M3 ;
      RECT 0 275.555 0.07 275.625 ;
    END
  END r0_rd_out[102]
  PIN r0_rd_out[103]
    DIRECTION OUTPUT ;
    USE SIGNAL ;
    SHAPE ABUTMENT ;
    PORT
      LAYER M3 ;
      RECT 0 276.675 0.07 276.745 ;
    END
  END r0_rd_out[103]
  PIN r0_rd_out[104]
    DIRECTION OUTPUT ;
    USE SIGNAL ;
    SHAPE ABUTMENT ;
    PORT
      LAYER M3 ;
      RECT 0 277.795 0.07 277.865 ;
    END
  END r0_rd_out[104]
  PIN r0_rd_out[105]
    DIRECTION OUTPUT ;
    USE SIGNAL ;
    SHAPE ABUTMENT ;
    PORT
      LAYER M3 ;
      RECT 0 278.915 0.07 278.985 ;
    END
  END r0_rd_out[105]
  PIN r0_rd_out[106]
    DIRECTION OUTPUT ;
    USE SIGNAL ;
    SHAPE ABUTMENT ;
    PORT
      LAYER M3 ;
      RECT 0 280.035 0.07 280.105 ;
    END
  END r0_rd_out[106]
  PIN r0_rd_out[107]
    DIRECTION OUTPUT ;
    USE SIGNAL ;
    SHAPE ABUTMENT ;
    PORT
      LAYER M3 ;
      RECT 0 281.155 0.07 281.225 ;
    END
  END r0_rd_out[107]
  PIN r0_rd_out[108]
    DIRECTION OUTPUT ;
    USE SIGNAL ;
    SHAPE ABUTMENT ;
    PORT
      LAYER M3 ;
      RECT 0 282.275 0.07 282.345 ;
    END
  END r0_rd_out[108]
  PIN r0_rd_out[109]
    DIRECTION OUTPUT ;
    USE SIGNAL ;
    SHAPE ABUTMENT ;
    PORT
      LAYER M3 ;
      RECT 0 283.395 0.07 283.465 ;
    END
  END r0_rd_out[109]
  PIN r0_rd_out[110]
    DIRECTION OUTPUT ;
    USE SIGNAL ;
    SHAPE ABUTMENT ;
    PORT
      LAYER M3 ;
      RECT 0 284.515 0.07 284.585 ;
    END
  END r0_rd_out[110]
  PIN r0_rd_out[111]
    DIRECTION OUTPUT ;
    USE SIGNAL ;
    SHAPE ABUTMENT ;
    PORT
      LAYER M3 ;
      RECT 0 285.635 0.07 285.705 ;
    END
  END r0_rd_out[111]
  PIN r0_rd_out[112]
    DIRECTION OUTPUT ;
    USE SIGNAL ;
    SHAPE ABUTMENT ;
    PORT
      LAYER M3 ;
      RECT 0 286.755 0.07 286.825 ;
    END
  END r0_rd_out[112]
  PIN r0_rd_out[113]
    DIRECTION OUTPUT ;
    USE SIGNAL ;
    SHAPE ABUTMENT ;
    PORT
      LAYER M3 ;
      RECT 0 287.875 0.07 287.945 ;
    END
  END r0_rd_out[113]
  PIN r0_rd_out[114]
    DIRECTION OUTPUT ;
    USE SIGNAL ;
    SHAPE ABUTMENT ;
    PORT
      LAYER M3 ;
      RECT 0 288.995 0.07 289.065 ;
    END
  END r0_rd_out[114]
  PIN r0_rd_out[115]
    DIRECTION OUTPUT ;
    USE SIGNAL ;
    SHAPE ABUTMENT ;
    PORT
      LAYER M3 ;
      RECT 0 290.115 0.07 290.185 ;
    END
  END r0_rd_out[115]
  PIN r0_rd_out[116]
    DIRECTION OUTPUT ;
    USE SIGNAL ;
    SHAPE ABUTMENT ;
    PORT
      LAYER M3 ;
      RECT 0 291.235 0.07 291.305 ;
    END
  END r0_rd_out[116]
  PIN r0_rd_out[117]
    DIRECTION OUTPUT ;
    USE SIGNAL ;
    SHAPE ABUTMENT ;
    PORT
      LAYER M3 ;
      RECT 0 292.355 0.07 292.425 ;
    END
  END r0_rd_out[117]
  PIN r0_rd_out[118]
    DIRECTION OUTPUT ;
    USE SIGNAL ;
    SHAPE ABUTMENT ;
    PORT
      LAYER M3 ;
      RECT 0 293.475 0.07 293.545 ;
    END
  END r0_rd_out[118]
  PIN r0_rd_out[119]
    DIRECTION OUTPUT ;
    USE SIGNAL ;
    SHAPE ABUTMENT ;
    PORT
      LAYER M3 ;
      RECT 0 294.595 0.07 294.665 ;
    END
  END r0_rd_out[119]
  PIN r0_rd_out[120]
    DIRECTION OUTPUT ;
    USE SIGNAL ;
    SHAPE ABUTMENT ;
    PORT
      LAYER M3 ;
      RECT 0 295.715 0.07 295.785 ;
    END
  END r0_rd_out[120]
  PIN r0_rd_out[121]
    DIRECTION OUTPUT ;
    USE SIGNAL ;
    SHAPE ABUTMENT ;
    PORT
      LAYER M3 ;
      RECT 0 296.835 0.07 296.905 ;
    END
  END r0_rd_out[121]
  PIN r0_rd_out[122]
    DIRECTION OUTPUT ;
    USE SIGNAL ;
    SHAPE ABUTMENT ;
    PORT
      LAYER M3 ;
      RECT 0 297.955 0.07 298.025 ;
    END
  END r0_rd_out[122]
  PIN r0_rd_out[123]
    DIRECTION OUTPUT ;
    USE SIGNAL ;
    SHAPE ABUTMENT ;
    PORT
      LAYER M3 ;
      RECT 0 299.075 0.07 299.145 ;
    END
  END r0_rd_out[123]
  PIN r0_rd_out[124]
    DIRECTION OUTPUT ;
    USE SIGNAL ;
    SHAPE ABUTMENT ;
    PORT
      LAYER M3 ;
      RECT 0 300.195 0.07 300.265 ;
    END
  END r0_rd_out[124]
  PIN r0_rd_out[125]
    DIRECTION OUTPUT ;
    USE SIGNAL ;
    SHAPE ABUTMENT ;
    PORT
      LAYER M3 ;
      RECT 0 301.315 0.07 301.385 ;
    END
  END r0_rd_out[125]
  PIN r0_rd_out[126]
    DIRECTION OUTPUT ;
    USE SIGNAL ;
    SHAPE ABUTMENT ;
    PORT
      LAYER M3 ;
      RECT 0 302.435 0.07 302.505 ;
    END
  END r0_rd_out[126]
  PIN r0_rd_out[127]
    DIRECTION OUTPUT ;
    USE SIGNAL ;
    SHAPE ABUTMENT ;
    PORT
      LAYER M3 ;
      RECT 0 303.555 0.07 303.625 ;
    END
  END r0_rd_out[127]
  PIN w0_addr_in[0]
    DIRECTION INPUT ;
    USE SIGNAL ;
    SHAPE ABUTMENT ;
    PORT
      LAYER M3 ;
      RECT 0 304.675 0.07 304.745 ;
    END
  END w0_addr_in[0]
  PIN w0_addr_in[1]
    DIRECTION INPUT ;
    USE SIGNAL ;
    SHAPE ABUTMENT ;
    PORT
      LAYER M3 ;
      RECT 0 305.795 0.07 305.865 ;
    END
  END w0_addr_in[1]
  PIN w0_addr_in[2]
    DIRECTION INPUT ;
    USE SIGNAL ;
    SHAPE ABUTMENT ;
    PORT
      LAYER M3 ;
      RECT 0 306.915 0.07 306.985 ;
    END
  END w0_addr_in[2]
  PIN w0_addr_in[3]
    DIRECTION INPUT ;
    USE SIGNAL ;
    SHAPE ABUTMENT ;
    PORT
      LAYER M3 ;
      RECT 0 308.035 0.07 308.105 ;
    END
  END w0_addr_in[3]
  PIN w0_addr_in[4]
    DIRECTION INPUT ;
    USE SIGNAL ;
    SHAPE ABUTMENT ;
    PORT
      LAYER M3 ;
      RECT 0 309.155 0.07 309.225 ;
    END
  END w0_addr_in[4]
  PIN w0_addr_in[5]
    DIRECTION INPUT ;
    USE SIGNAL ;
    SHAPE ABUTMENT ;
    PORT
      LAYER M3 ;
      RECT 0 310.275 0.07 310.345 ;
    END
  END w0_addr_in[5]
  PIN w0_addr_in[6]
    DIRECTION INPUT ;
    USE SIGNAL ;
    SHAPE ABUTMENT ;
    PORT
      LAYER M3 ;
      RECT 0 311.395 0.07 311.465 ;
    END
  END w0_addr_in[6]
  PIN w0_addr_in[7]
    DIRECTION INPUT ;
    USE SIGNAL ;
    SHAPE ABUTMENT ;
    PORT
      LAYER M3 ;
      RECT 0 312.515 0.07 312.585 ;
    END
  END w0_addr_in[7]
  PIN w0_addr_in[8]
    DIRECTION INPUT ;
    USE SIGNAL ;
    SHAPE ABUTMENT ;
    PORT
      LAYER M3 ;
      RECT 0 313.635 0.07 313.705 ;
    END
  END w0_addr_in[8]
  PIN r0_addr_in[0]
    DIRECTION INPUT ;
    USE SIGNAL ;
    SHAPE ABUTMENT ;
    PORT
      LAYER M3 ;
      RECT 0 314.755 0.07 314.825 ;
    END
  END r0_addr_in[0]
  PIN r0_addr_in[1]
    DIRECTION INPUT ;
    USE SIGNAL ;
    SHAPE ABUTMENT ;
    PORT
      LAYER M3 ;
      RECT 0 315.875 0.07 315.945 ;
    END
  END r0_addr_in[1]
  PIN r0_addr_in[2]
    DIRECTION INPUT ;
    USE SIGNAL ;
    SHAPE ABUTMENT ;
    PORT
      LAYER M3 ;
      RECT 0 316.995 0.07 317.065 ;
    END
  END r0_addr_in[2]
  PIN r0_addr_in[3]
    DIRECTION INPUT ;
    USE SIGNAL ;
    SHAPE ABUTMENT ;
    PORT
      LAYER M3 ;
      RECT 0 318.115 0.07 318.185 ;
    END
  END r0_addr_in[3]
  PIN r0_addr_in[4]
    DIRECTION INPUT ;
    USE SIGNAL ;
    SHAPE ABUTMENT ;
    PORT
      LAYER M3 ;
      RECT 0 319.235 0.07 319.305 ;
    END
  END r0_addr_in[4]
  PIN r0_addr_in[5]
    DIRECTION INPUT ;
    USE SIGNAL ;
    SHAPE ABUTMENT ;
    PORT
      LAYER M3 ;
      RECT 0 320.355 0.07 320.425 ;
    END
  END r0_addr_in[5]
  PIN r0_addr_in[6]
    DIRECTION INPUT ;
    USE SIGNAL ;
    SHAPE ABUTMENT ;
    PORT
      LAYER M3 ;
      RECT 0 321.475 0.07 321.545 ;
    END
  END r0_addr_in[6]
  PIN r0_addr_in[7]
    DIRECTION INPUT ;
    USE SIGNAL ;
    SHAPE ABUTMENT ;
    PORT
      LAYER M3 ;
      RECT 0 322.595 0.07 322.665 ;
    END
  END r0_addr_in[7]
  PIN r0_addr_in[8]
    DIRECTION INPUT ;
    USE SIGNAL ;
    SHAPE ABUTMENT ;
    PORT
      LAYER M3 ;
      RECT 0 323.715 0.07 323.785 ;
    END
  END r0_addr_in[8]
  PIN w0_we_in
    DIRECTION INPUT ;
    USE SIGNAL ;
    SHAPE ABUTMENT ;
    PORT
      LAYER M3 ;
      RECT 0 324.835 0.07 324.905 ;
    END
  END w0_we_in
  PIN w0_ce_in
    DIRECTION INPUT ;
    USE SIGNAL ;
    SHAPE ABUTMENT ;
    PORT
      LAYER M3 ;
      RECT 0 325.955 0.07 326.025 ;
    END
  END w0_ce_in
  PIN w0_clk
    DIRECTION INPUT ;
    USE SIGNAL ;
    SHAPE ABUTMENT ;
    PORT
      LAYER M3 ;
      RECT 0 327.075 0.07 327.145 ;
    END
  END w0_clk
  PIN r0_ce_in
    DIRECTION INPUT ;
    USE SIGNAL ;
    SHAPE ABUTMENT ;
    PORT
      LAYER M3 ;
      RECT 0 328.195 0.07 328.265 ;
    END
  END r0_ce_in
  PIN r0_clk
    DIRECTION INPUT ;
    USE SIGNAL ;
    SHAPE ABUTMENT ;
    PORT
      LAYER M3 ;
      RECT 0 329.315 0.07 329.385 ;
    END
  END r0_clk
  PIN VSS
    DIRECTION INOUT ;
    USE GROUND ;
    PORT
      LAYER M4 ;
      RECT 1 0.84 1.28 353.36 ;
      RECT 3.24 0.84 3.52 353.36 ;
      RECT 5.48 0.84 5.76 353.36 ;
      RECT 7.72 0.84 8 353.36 ;
      RECT 9.96 0.84 10.24 353.36 ;
      RECT 12.2 0.84 12.48 353.36 ;
      RECT 14.44 0.84 14.72 353.36 ;
      RECT 16.68 0.84 16.96 353.36 ;
      RECT 18.92 0.84 19.2 353.36 ;
      RECT 21.16 0.84 21.44 353.36 ;
      RECT 23.4 0.84 23.68 353.36 ;
      RECT 25.64 0.84 25.92 353.36 ;
      RECT 27.88 0.84 28.16 353.36 ;
      RECT 30.12 0.84 30.4 353.36 ;
      RECT 32.36 0.84 32.64 353.36 ;
      RECT 34.6 0.84 34.88 353.36 ;
      RECT 36.84 0.84 37.12 353.36 ;
      RECT 39.08 0.84 39.36 353.36 ;
      RECT 41.32 0.84 41.6 353.36 ;
      RECT 43.56 0.84 43.84 353.36 ;
      RECT 45.8 0.84 46.08 353.36 ;
      RECT 48.04 0.84 48.32 353.36 ;
      RECT 50.28 0.84 50.56 353.36 ;
      RECT 52.52 0.84 52.8 353.36 ;
      RECT 54.76 0.84 55.04 353.36 ;
      RECT 57 0.84 57.28 353.36 ;
      RECT 59.24 0.84 59.52 353.36 ;
      RECT 61.48 0.84 61.76 353.36 ;
      RECT 63.72 0.84 64 353.36 ;
      RECT 65.96 0.84 66.24 353.36 ;
      RECT 68.2 0.84 68.48 353.36 ;
      RECT 70.44 0.84 70.72 353.36 ;
      RECT 72.68 0.84 72.96 353.36 ;
      RECT 74.92 0.84 75.2 353.36 ;
      RECT 77.16 0.84 77.44 353.36 ;
      RECT 79.4 0.84 79.68 353.36 ;
      RECT 81.64 0.84 81.92 353.36 ;
      RECT 83.88 0.84 84.16 353.36 ;
      RECT 86.12 0.84 86.4 353.36 ;
      RECT 88.36 0.84 88.64 353.36 ;
      RECT 90.6 0.84 90.88 353.36 ;
      RECT 92.84 0.84 93.12 353.36 ;
      RECT 95.08 0.84 95.36 353.36 ;
      RECT 97.32 0.84 97.6 353.36 ;
      RECT 99.56 0.84 99.84 353.36 ;
      RECT 101.8 0.84 102.08 353.36 ;
      RECT 104.04 0.84 104.32 353.36 ;
      RECT 106.28 0.84 106.56 353.36 ;
      RECT 108.52 0.84 108.8 353.36 ;
      RECT 110.76 0.84 111.04 353.36 ;
      RECT 113 0.84 113.28 353.36 ;
      RECT 115.24 0.84 115.52 353.36 ;
      RECT 117.48 0.84 117.76 353.36 ;
      RECT 119.72 0.84 120 353.36 ;
      RECT 121.96 0.84 122.24 353.36 ;
      RECT 124.2 0.84 124.48 353.36 ;
      RECT 126.44 0.84 126.72 353.36 ;
      RECT 128.68 0.84 128.96 353.36 ;
      RECT 130.92 0.84 131.2 353.36 ;
      RECT 133.16 0.84 133.44 353.36 ;
      RECT 135.4 0.84 135.68 353.36 ;
      RECT 137.64 0.84 137.92 353.36 ;
      RECT 139.88 0.84 140.16 353.36 ;
      RECT 142.12 0.84 142.4 353.36 ;
      RECT 144.36 0.84 144.64 353.36 ;
      RECT 146.6 0.84 146.88 353.36 ;
      RECT 148.84 0.84 149.12 353.36 ;
      RECT 151.08 0.84 151.36 353.36 ;
      RECT 153.32 0.84 153.6 353.36 ;
      RECT 155.56 0.84 155.84 353.36 ;
      RECT 157.8 0.84 158.08 353.36 ;
      RECT 160.04 0.84 160.32 353.36 ;
      RECT 162.28 0.84 162.56 353.36 ;
      RECT 164.52 0.84 164.8 353.36 ;
      RECT 166.76 0.84 167.04 353.36 ;
      RECT 169 0.84 169.28 353.36 ;
      RECT 171.24 0.84 171.52 353.36 ;
      RECT 173.48 0.84 173.76 353.36 ;
      RECT 175.72 0.84 176 353.36 ;
      RECT 177.96 0.84 178.24 353.36 ;
      RECT 180.2 0.84 180.48 353.36 ;
      RECT 182.44 0.84 182.72 353.36 ;
      RECT 184.68 0.84 184.96 353.36 ;
      RECT 186.92 0.84 187.2 353.36 ;
      RECT 189.16 0.84 189.44 353.36 ;
      RECT 191.4 0.84 191.68 353.36 ;
      RECT 193.64 0.84 193.92 353.36 ;
      RECT 195.88 0.84 196.16 353.36 ;
      RECT 198.12 0.84 198.4 353.36 ;
      RECT 200.36 0.84 200.64 353.36 ;
      RECT 202.6 0.84 202.88 353.36 ;
      RECT 204.84 0.84 205.12 353.36 ;
      RECT 207.08 0.84 207.36 353.36 ;
      RECT 209.32 0.84 209.6 353.36 ;
      RECT 211.56 0.84 211.84 353.36 ;
      RECT 213.8 0.84 214.08 353.36 ;
      RECT 216.04 0.84 216.32 353.36 ;
      RECT 218.28 0.84 218.56 353.36 ;
      RECT 220.52 0.84 220.8 353.36 ;
      RECT 222.76 0.84 223.04 353.36 ;
      RECT 225 0.84 225.28 353.36 ;
      RECT 227.24 0.84 227.52 353.36 ;
      RECT 229.48 0.84 229.76 353.36 ;
      RECT 231.72 0.84 232 353.36 ;
      RECT 233.96 0.84 234.24 353.36 ;
      RECT 236.2 0.84 236.48 353.36 ;
      RECT 238.44 0.84 238.72 353.36 ;
      RECT 240.68 0.84 240.96 353.36 ;
      RECT 242.92 0.84 243.2 353.36 ;
      RECT 245.16 0.84 245.44 353.36 ;
      RECT 247.4 0.84 247.68 353.36 ;
      RECT 249.64 0.84 249.92 353.36 ;
      RECT 251.88 0.84 252.16 353.36 ;
      RECT 254.12 0.84 254.4 353.36 ;
      RECT 256.36 0.84 256.64 353.36 ;
      RECT 258.6 0.84 258.88 353.36 ;
      RECT 260.84 0.84 261.12 353.36 ;
      RECT 263.08 0.84 263.36 353.36 ;
      RECT 265.32 0.84 265.6 353.36 ;
      RECT 267.56 0.84 267.84 353.36 ;
      RECT 269.8 0.84 270.08 353.36 ;
      RECT 272.04 0.84 272.32 353.36 ;
      RECT 274.28 0.84 274.56 353.36 ;
      RECT 276.52 0.84 276.8 353.36 ;
      RECT 278.76 0.84 279.04 353.36 ;
      RECT 281 0.84 281.28 353.36 ;
      RECT 283.24 0.84 283.52 353.36 ;
      RECT 285.48 0.84 285.76 353.36 ;
      RECT 287.72 0.84 288 353.36 ;
      RECT 289.96 0.84 290.24 353.36 ;
      RECT 292.2 0.84 292.48 353.36 ;
    END
  END VSS
  PIN VDD
    DIRECTION INOUT ;
    USE POWER ;
    PORT
      LAYER M4 ;
      RECT 2.12 0.84 2.4 353.36 ;
      RECT 4.36 0.84 4.64 353.36 ;
      RECT 6.6 0.84 6.88 353.36 ;
      RECT 8.84 0.84 9.12 353.36 ;
      RECT 11.08 0.84 11.36 353.36 ;
      RECT 13.32 0.84 13.6 353.36 ;
      RECT 15.56 0.84 15.84 353.36 ;
      RECT 17.8 0.84 18.08 353.36 ;
      RECT 20.04 0.84 20.32 353.36 ;
      RECT 22.28 0.84 22.56 353.36 ;
      RECT 24.52 0.84 24.8 353.36 ;
      RECT 26.76 0.84 27.04 353.36 ;
      RECT 29 0.84 29.28 353.36 ;
      RECT 31.24 0.84 31.52 353.36 ;
      RECT 33.48 0.84 33.76 353.36 ;
      RECT 35.72 0.84 36 353.36 ;
      RECT 37.96 0.84 38.24 353.36 ;
      RECT 40.2 0.84 40.48 353.36 ;
      RECT 42.44 0.84 42.72 353.36 ;
      RECT 44.68 0.84 44.96 353.36 ;
      RECT 46.92 0.84 47.2 353.36 ;
      RECT 49.16 0.84 49.44 353.36 ;
      RECT 51.4 0.84 51.68 353.36 ;
      RECT 53.64 0.84 53.92 353.36 ;
      RECT 55.88 0.84 56.16 353.36 ;
      RECT 58.12 0.84 58.4 353.36 ;
      RECT 60.36 0.84 60.64 353.36 ;
      RECT 62.6 0.84 62.88 353.36 ;
      RECT 64.84 0.84 65.12 353.36 ;
      RECT 67.08 0.84 67.36 353.36 ;
      RECT 69.32 0.84 69.6 353.36 ;
      RECT 71.56 0.84 71.84 353.36 ;
      RECT 73.8 0.84 74.08 353.36 ;
      RECT 76.04 0.84 76.32 353.36 ;
      RECT 78.28 0.84 78.56 353.36 ;
      RECT 80.52 0.84 80.8 353.36 ;
      RECT 82.76 0.84 83.04 353.36 ;
      RECT 85 0.84 85.28 353.36 ;
      RECT 87.24 0.84 87.52 353.36 ;
      RECT 89.48 0.84 89.76 353.36 ;
      RECT 91.72 0.84 92 353.36 ;
      RECT 93.96 0.84 94.24 353.36 ;
      RECT 96.2 0.84 96.48 353.36 ;
      RECT 98.44 0.84 98.72 353.36 ;
      RECT 100.68 0.84 100.96 353.36 ;
      RECT 102.92 0.84 103.2 353.36 ;
      RECT 105.16 0.84 105.44 353.36 ;
      RECT 107.4 0.84 107.68 353.36 ;
      RECT 109.64 0.84 109.92 353.36 ;
      RECT 111.88 0.84 112.16 353.36 ;
      RECT 114.12 0.84 114.4 353.36 ;
      RECT 116.36 0.84 116.64 353.36 ;
      RECT 118.6 0.84 118.88 353.36 ;
      RECT 120.84 0.84 121.12 353.36 ;
      RECT 123.08 0.84 123.36 353.36 ;
      RECT 125.32 0.84 125.6 353.36 ;
      RECT 127.56 0.84 127.84 353.36 ;
      RECT 129.8 0.84 130.08 353.36 ;
      RECT 132.04 0.84 132.32 353.36 ;
      RECT 134.28 0.84 134.56 353.36 ;
      RECT 136.52 0.84 136.8 353.36 ;
      RECT 138.76 0.84 139.04 353.36 ;
      RECT 141 0.84 141.28 353.36 ;
      RECT 143.24 0.84 143.52 353.36 ;
      RECT 145.48 0.84 145.76 353.36 ;
      RECT 147.72 0.84 148 353.36 ;
      RECT 149.96 0.84 150.24 353.36 ;
      RECT 152.2 0.84 152.48 353.36 ;
      RECT 154.44 0.84 154.72 353.36 ;
      RECT 156.68 0.84 156.96 353.36 ;
      RECT 158.92 0.84 159.2 353.36 ;
      RECT 161.16 0.84 161.44 353.36 ;
      RECT 163.4 0.84 163.68 353.36 ;
      RECT 165.64 0.84 165.92 353.36 ;
      RECT 167.88 0.84 168.16 353.36 ;
      RECT 170.12 0.84 170.4 353.36 ;
      RECT 172.36 0.84 172.64 353.36 ;
      RECT 174.6 0.84 174.88 353.36 ;
      RECT 176.84 0.84 177.12 353.36 ;
      RECT 179.08 0.84 179.36 353.36 ;
      RECT 181.32 0.84 181.6 353.36 ;
      RECT 183.56 0.84 183.84 353.36 ;
      RECT 185.8 0.84 186.08 353.36 ;
      RECT 188.04 0.84 188.32 353.36 ;
      RECT 190.28 0.84 190.56 353.36 ;
      RECT 192.52 0.84 192.8 353.36 ;
      RECT 194.76 0.84 195.04 353.36 ;
      RECT 197 0.84 197.28 353.36 ;
      RECT 199.24 0.84 199.52 353.36 ;
      RECT 201.48 0.84 201.76 353.36 ;
      RECT 203.72 0.84 204 353.36 ;
      RECT 205.96 0.84 206.24 353.36 ;
      RECT 208.2 0.84 208.48 353.36 ;
      RECT 210.44 0.84 210.72 353.36 ;
      RECT 212.68 0.84 212.96 353.36 ;
      RECT 214.92 0.84 215.2 353.36 ;
      RECT 217.16 0.84 217.44 353.36 ;
      RECT 219.4 0.84 219.68 353.36 ;
      RECT 221.64 0.84 221.92 353.36 ;
      RECT 223.88 0.84 224.16 353.36 ;
      RECT 226.12 0.84 226.4 353.36 ;
      RECT 228.36 0.84 228.64 353.36 ;
      RECT 230.6 0.84 230.88 353.36 ;
      RECT 232.84 0.84 233.12 353.36 ;
      RECT 235.08 0.84 235.36 353.36 ;
      RECT 237.32 0.84 237.6 353.36 ;
      RECT 239.56 0.84 239.84 353.36 ;
      RECT 241.8 0.84 242.08 353.36 ;
      RECT 244.04 0.84 244.32 353.36 ;
      RECT 246.28 0.84 246.56 353.36 ;
      RECT 248.52 0.84 248.8 353.36 ;
      RECT 250.76 0.84 251.04 353.36 ;
      RECT 253 0.84 253.28 353.36 ;
      RECT 255.24 0.84 255.52 353.36 ;
      RECT 257.48 0.84 257.76 353.36 ;
      RECT 259.72 0.84 260 353.36 ;
      RECT 261.96 0.84 262.24 353.36 ;
      RECT 264.2 0.84 264.48 353.36 ;
      RECT 266.44 0.84 266.72 353.36 ;
      RECT 268.68 0.84 268.96 353.36 ;
      RECT 270.92 0.84 271.2 353.36 ;
      RECT 273.16 0.84 273.44 353.36 ;
      RECT 275.4 0.84 275.68 353.36 ;
      RECT 277.64 0.84 277.92 353.36 ;
      RECT 279.88 0.84 280.16 353.36 ;
      RECT 282.12 0.84 282.4 353.36 ;
      RECT 284.36 0.84 284.64 353.36 ;
      RECT 286.6 0.84 286.88 353.36 ;
      RECT 288.84 0.84 289.12 353.36 ;
      RECT 291.08 0.84 291.36 353.36 ;
      RECT 293.32 0.84 293.6 353.36 ;
    END
  END VDD
  OBS
    LAYER M1 ;
    RECT 0 0 294.12 354.2 ;
    LAYER M2 ;
    RECT 0 0 294.12 354.2 ;
  END
END ht45_leon3vtabus_vta_q_512x128

END LIBRARY
